VERSION 5.8 ;
BUSBITCHARS "[]" ;
DIVIDERCHAR "/" ;
UNITS
  DATABASE MICRONS 2000 ;
END UNITS
MANUFACTURINGGRID 0.005 ;

SITE core
  CLASS CORE ;
  SIZE 0.2 BY 1.4 ;
END core

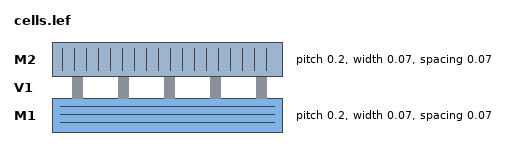
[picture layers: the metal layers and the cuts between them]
LAYER M1
  TYPE ROUTING ;
  DIRECTION HORIZONTAL ;
  PITCH 0.2 ;
  WIDTH 0.07 ;
  SPACING 0.07 ;
  RESISTANCE RPERSQ 0.38 ;
END M1

LAYER V1
  TYPE CUT ;
END V1

LAYER M2
  TYPE ROUTING ;
  DIRECTION VERTICAL ;
  PITCH 0.2 ;
  WIDTH 0.07 ;
  SPACING 0.07 ;
  RESISTANCE RPERSQ 0.25 ;
END M2

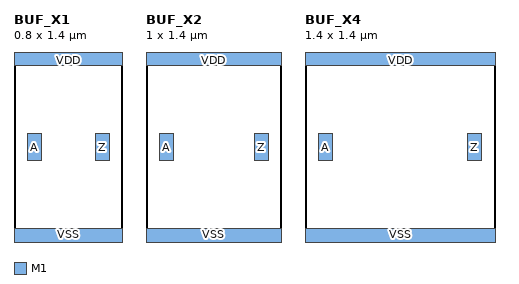
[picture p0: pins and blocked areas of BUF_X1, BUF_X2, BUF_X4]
MACRO BUF_X1
  CLASS CORE ;
  ORIGIN 0 0 ;
  SIZE 0.8 BY 1.4 ;
  SITE core ;
  PIN A
    DIRECTION INPUT ;
    USE SIGNAL ;
    PORT
      LAYER M1 ;
        RECT 0.1 0.6 0.2 0.8 ;
    END
  END A
  PIN Z
    DIRECTION OUTPUT ;
    USE SIGNAL ;
    PORT
      LAYER M1 ;
        RECT 0.6 0.6 0.7 0.8 ;
    END
  END Z
  PIN VDD
    DIRECTION INOUT ;
    USE POWER ;
    PORT
      LAYER M1 ;
        RECT 0 1.3 0.8 1.4 ;
    END
  END VDD
  PIN VSS
    DIRECTION INOUT ;
    USE GROUND ;
    PORT
      LAYER M1 ;
        RECT 0 0 0.8 0.1 ;
    END
  END VSS
END BUF_X1

MACRO BUF_X2
  CLASS CORE ;
  ORIGIN 0 0 ;
  SIZE 1.0 BY 1.4 ;
  SITE core ;
  PIN A
    DIRECTION INPUT ;
    USE SIGNAL ;
    PORT
      LAYER M1 ;
        RECT 0.1 0.6 0.2 0.8 ;
    END
  END A
  PIN Z
    DIRECTION OUTPUT ;
    USE SIGNAL ;
    PORT
      LAYER M1 ;
        RECT 0.8 0.6 0.9 0.8 ;
    END
  END Z
  PIN VDD
    DIRECTION INOUT ;
    USE POWER ;
    PORT
      LAYER M1 ;
        RECT 0 1.3 1.0 1.4 ;
    END
  END VDD
  PIN VSS
    DIRECTION INOUT ;
    USE GROUND ;
    PORT
      LAYER M1 ;
        RECT 0 0 1.0 0.1 ;
    END
  END VSS
END BUF_X2

MACRO BUF_X4
  CLASS CORE ;
  ORIGIN 0 0 ;
  SIZE 1.4 BY 1.4 ;
  SITE core ;
  PIN A
    DIRECTION INPUT ;
    USE SIGNAL ;
    PORT
      LAYER M1 ;
        RECT 0.1 0.6 0.2 0.8 ;
    END
  END A
  PIN Z
    DIRECTION OUTPUT ;
    USE SIGNAL ;
    PORT
      LAYER M1 ;
        RECT 1.2 0.6 1.3 0.8 ;
    END
  END Z
  PIN VDD
    DIRECTION INOUT ;
    USE POWER ;
    PORT
      LAYER M1 ;
        RECT 0 1.3 1.4 1.4 ;
    END
  END VDD
  PIN VSS
    DIRECTION INOUT ;
    USE GROUND ;
    PORT
      LAYER M1 ;
        RECT 0 0 1.4 0.1 ;
    END
  END VSS
END BUF_X4

END LIBRARY
